# OpenTallas memory compiler (tools/mem_compiler), ASAP7 abstract view
VERSION 5.7 ;
BUSBITCHARS "[]" ;
DIVIDERCHAR "/" ;
PROPERTYDEFINITIONS
  MACRO width INTEGER ;
  MACRO depth INTEGER ;
  MACRO banks INTEGER ;
END PROPERTYDEFINITIONS
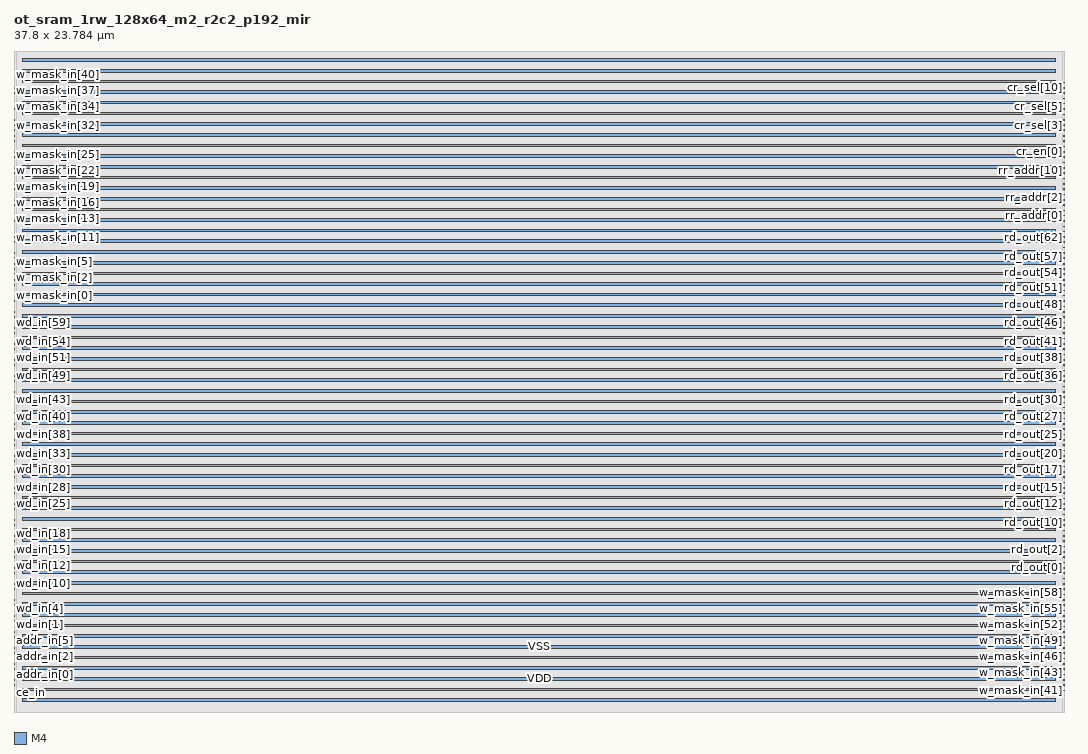
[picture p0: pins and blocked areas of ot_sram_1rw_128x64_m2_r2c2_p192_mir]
MACRO ot_sram_1rw_128x64_m2_r2c2_p192_mir
  PROPERTY width 64 ;
  PROPERTY depth 128 ;
  PROPERTY banks 1 ;
  FOREIGN ot_sram_1rw_128x64_m2_r2c2_p192_mir 0 0 ;
  SYMMETRY X Y R90 ;
  SIZE 37.800 BY 23.784 ;
  CLASS BLOCK ;
  PIN clk
    DIRECTION INPUT ;
    USE CLOCK ;
    SHAPE ABUTMENT ;
    PORT
      LAYER M4 ;
      RECT 0.000 0.768 0.024 0.792 ;
    END
  END clk
  PIN ce_in
    DIRECTION INPUT ;
    USE SIGNAL ;
    SHAPE ABUTMENT ;
    PORT
      LAYER M4 ;
      RECT 0.000 0.960 0.024 0.984 ;
    END
  END ce_in
  PIN we_in
    DIRECTION INPUT ;
    USE SIGNAL ;
    SHAPE ABUTMENT ;
    PORT
      LAYER M4 ;
      RECT 0.000 1.152 0.024 1.176 ;
    END
  END we_in
  PIN addr_in[0]
    DIRECTION INPUT ;
    USE SIGNAL ;
    SHAPE ABUTMENT ;
    PORT
      LAYER M4 ;
      RECT 0.000 1.344 0.024 1.368 ;
    END
  END addr_in[0]
  PIN addr_in[1]
    DIRECTION INPUT ;
    USE SIGNAL ;
    SHAPE ABUTMENT ;
    PORT
      LAYER M4 ;
      RECT 0.000 1.536 0.024 1.560 ;
    END
  END addr_in[1]
  PIN addr_in[2]
    DIRECTION INPUT ;
    USE SIGNAL ;
    SHAPE ABUTMENT ;
    PORT
      LAYER M4 ;
      RECT 0.000 1.728 0.024 1.752 ;
    END
  END addr_in[2]
  PIN addr_in[3]
    DIRECTION INPUT ;
    USE SIGNAL ;
    SHAPE ABUTMENT ;
    PORT
      LAYER M4 ;
      RECT 0.000 1.920 0.024 1.944 ;
    END
  END addr_in[3]
  PIN addr_in[4]
    DIRECTION INPUT ;
    USE SIGNAL ;
    SHAPE ABUTMENT ;
    PORT
      LAYER M4 ;
      RECT 0.000 2.112 0.024 2.136 ;
    END
  END addr_in[4]
  PIN addr_in[5]
    DIRECTION INPUT ;
    USE SIGNAL ;
    SHAPE ABUTMENT ;
    PORT
      LAYER M4 ;
      RECT 0.000 2.304 0.024 2.328 ;
    END
  END addr_in[5]
  PIN addr_in[6]
    DIRECTION INPUT ;
    USE SIGNAL ;
    SHAPE ABUTMENT ;
    PORT
      LAYER M4 ;
      RECT 0.000 2.496 0.024 2.520 ;
    END
  END addr_in[6]
  PIN wd_in[0]
    DIRECTION INPUT ;
    USE SIGNAL ;
    SHAPE ABUTMENT ;
    PORT
      LAYER M4 ;
      RECT 0.000 2.688 0.024 2.712 ;
    END
  END wd_in[0]
  PIN wd_in[1]
    DIRECTION INPUT ;
    USE SIGNAL ;
    SHAPE ABUTMENT ;
    PORT
      LAYER M4 ;
      RECT 0.000 2.880 0.024 2.904 ;
    END
  END wd_in[1]
  PIN wd_in[2]
    DIRECTION INPUT ;
    USE SIGNAL ;
    SHAPE ABUTMENT ;
    PORT
      LAYER M4 ;
      RECT 0.000 3.072 0.024 3.096 ;
    END
  END wd_in[2]
  PIN wd_in[3]
    DIRECTION INPUT ;
    USE SIGNAL ;
    SHAPE ABUTMENT ;
    PORT
      LAYER M4 ;
      RECT 0.000 3.264 0.024 3.288 ;
    END
  END wd_in[3]
  PIN wd_in[4]
    DIRECTION INPUT ;
    USE SIGNAL ;
    SHAPE ABUTMENT ;
    PORT
      LAYER M4 ;
      RECT 0.000 3.456 0.024 3.480 ;
    END
  END wd_in[4]
  PIN wd_in[5]
    DIRECTION INPUT ;
    USE SIGNAL ;
    SHAPE ABUTMENT ;
    PORT
      LAYER M4 ;
      RECT 0.000 3.648 0.024 3.672 ;
    END
  END wd_in[5]
  PIN wd_in[6]
    DIRECTION INPUT ;
    USE SIGNAL ;
    SHAPE ABUTMENT ;
    PORT
      LAYER M4 ;
      RECT 0.000 3.840 0.024 3.864 ;
    END
  END wd_in[6]
  PIN wd_in[7]
    DIRECTION INPUT ;
    USE SIGNAL ;
    SHAPE ABUTMENT ;
    PORT
      LAYER M4 ;
      RECT 0.000 4.032 0.024 4.056 ;
    END
  END wd_in[7]
  PIN wd_in[8]
    DIRECTION INPUT ;
    USE SIGNAL ;
    SHAPE ABUTMENT ;
    PORT
      LAYER M4 ;
      RECT 0.000 4.224 0.024 4.248 ;
    END
  END wd_in[8]
  PIN wd_in[9]
    DIRECTION INPUT ;
    USE SIGNAL ;
    SHAPE ABUTMENT ;
    PORT
      LAYER M4 ;
      RECT 0.000 4.416 0.024 4.440 ;
    END
  END wd_in[9]
  PIN wd_in[10]
    DIRECTION INPUT ;
    USE SIGNAL ;
    SHAPE ABUTMENT ;
    PORT
      LAYER M4 ;
      RECT 0.000 4.608 0.024 4.632 ;
    END
  END wd_in[10]
  PIN wd_in[11]
    DIRECTION INPUT ;
    USE SIGNAL ;
    SHAPE ABUTMENT ;
    PORT
      LAYER M4 ;
      RECT 0.000 4.800 0.024 4.824 ;
    END
  END wd_in[11]
  PIN wd_in[12]
    DIRECTION INPUT ;
    USE SIGNAL ;
    SHAPE ABUTMENT ;
    PORT
      LAYER M4 ;
      RECT 0.000 4.992 0.024 5.016 ;
    END
  END wd_in[12]
  PIN wd_in[13]
    DIRECTION INPUT ;
    USE SIGNAL ;
    SHAPE ABUTMENT ;
    PORT
      LAYER M4 ;
      RECT 0.000 5.184 0.024 5.208 ;
    END
  END wd_in[13]
  PIN wd_in[14]
    DIRECTION INPUT ;
    USE SIGNAL ;
    SHAPE ABUTMENT ;
    PORT
      LAYER M4 ;
      RECT 0.000 5.376 0.024 5.400 ;
    END
  END wd_in[14]
  PIN wd_in[15]
    DIRECTION INPUT ;
    USE SIGNAL ;
    SHAPE ABUTMENT ;
    PORT
      LAYER M4 ;
      RECT 0.000 5.568 0.024 5.592 ;
    END
  END wd_in[15]
  PIN wd_in[16]
    DIRECTION INPUT ;
    USE SIGNAL ;
    SHAPE ABUTMENT ;
    PORT
      LAYER M4 ;
      RECT 0.000 5.760 0.024 5.784 ;
    END
  END wd_in[16]
  PIN wd_in[17]
    DIRECTION INPUT ;
    USE SIGNAL ;
    SHAPE ABUTMENT ;
    PORT
      LAYER M4 ;
      RECT 0.000 5.952 0.024 5.976 ;
    END
  END wd_in[17]
  PIN wd_in[18]
    DIRECTION INPUT ;
    USE SIGNAL ;
    SHAPE ABUTMENT ;
    PORT
      LAYER M4 ;
      RECT 0.000 6.144 0.024 6.168 ;
    END
  END wd_in[18]
  PIN wd_in[19]
    DIRECTION INPUT ;
    USE SIGNAL ;
    SHAPE ABUTMENT ;
    PORT
      LAYER M4 ;
      RECT 0.000 6.336 0.024 6.360 ;
    END
  END wd_in[19]
  PIN wd_in[20]
    DIRECTION INPUT ;
    USE SIGNAL ;
    SHAPE ABUTMENT ;
    PORT
      LAYER M4 ;
      RECT 0.000 6.528 0.024 6.552 ;
    END
  END wd_in[20]
  PIN wd_in[21]
    DIRECTION INPUT ;
    USE SIGNAL ;
    SHAPE ABUTMENT ;
    PORT
      LAYER M4 ;
      RECT 0.000 6.720 0.024 6.744 ;
    END
  END wd_in[21]
  PIN wd_in[22]
    DIRECTION INPUT ;
    USE SIGNAL ;
    SHAPE ABUTMENT ;
    PORT
      LAYER M4 ;
      RECT 0.000 6.912 0.024 6.936 ;
    END
  END wd_in[22]
  PIN wd_in[23]
    DIRECTION INPUT ;
    USE SIGNAL ;
    SHAPE ABUTMENT ;
    PORT
      LAYER M4 ;
      RECT 0.000 7.104 0.024 7.128 ;
    END
  END wd_in[23]
  PIN wd_in[24]
    DIRECTION INPUT ;
    USE SIGNAL ;
    SHAPE ABUTMENT ;
    PORT
      LAYER M4 ;
      RECT 0.000 7.296 0.024 7.320 ;
    END
  END wd_in[24]
  PIN wd_in[25]
    DIRECTION INPUT ;
    USE SIGNAL ;
    SHAPE ABUTMENT ;
    PORT
      LAYER M4 ;
      RECT 0.000 7.488 0.024 7.512 ;
    END
  END wd_in[25]
  PIN wd_in[26]
    DIRECTION INPUT ;
    USE SIGNAL ;
    SHAPE ABUTMENT ;
    PORT
      LAYER M4 ;
      RECT 0.000 7.680 0.024 7.704 ;
    END
  END wd_in[26]
  PIN wd_in[27]
    DIRECTION INPUT ;
    USE SIGNAL ;
    SHAPE ABUTMENT ;
    PORT
      LAYER M4 ;
      RECT 0.000 7.872 0.024 7.896 ;
    END
  END wd_in[27]
  PIN wd_in[28]
    DIRECTION INPUT ;
    USE SIGNAL ;
    SHAPE ABUTMENT ;
    PORT
      LAYER M4 ;
      RECT 0.000 8.064 0.024 8.088 ;
    END
  END wd_in[28]
  PIN wd_in[29]
    DIRECTION INPUT ;
    USE SIGNAL ;
    SHAPE ABUTMENT ;
    PORT
      LAYER M4 ;
      RECT 0.000 8.256 0.024 8.280 ;
    END
  END wd_in[29]
  PIN wd_in[30]
    DIRECTION INPUT ;
    USE SIGNAL ;
    SHAPE ABUTMENT ;
    PORT
      LAYER M4 ;
      RECT 0.000 8.448 0.024 8.472 ;
    END
  END wd_in[30]
  PIN wd_in[31]
    DIRECTION INPUT ;
    USE SIGNAL ;
    SHAPE ABUTMENT ;
    PORT
      LAYER M4 ;
      RECT 0.000 8.640 0.024 8.664 ;
    END
  END wd_in[31]
  PIN wd_in[32]
    DIRECTION INPUT ;
    USE SIGNAL ;
    SHAPE ABUTMENT ;
    PORT
      LAYER M4 ;
      RECT 0.000 8.832 0.024 8.856 ;
    END
  END wd_in[32]
  PIN wd_in[33]
    DIRECTION INPUT ;
    USE SIGNAL ;
    SHAPE ABUTMENT ;
    PORT
      LAYER M4 ;
      RECT 0.000 9.024 0.024 9.048 ;
    END
  END wd_in[33]
  PIN wd_in[34]
    DIRECTION INPUT ;
    USE SIGNAL ;
    SHAPE ABUTMENT ;
    PORT
      LAYER M4 ;
      RECT 0.000 9.216 0.024 9.240 ;
    END
  END wd_in[34]
  PIN wd_in[35]
    DIRECTION INPUT ;
    USE SIGNAL ;
    SHAPE ABUTMENT ;
    PORT
      LAYER M4 ;
      RECT 0.000 9.408 0.024 9.432 ;
    END
  END wd_in[35]
  PIN wd_in[36]
    DIRECTION INPUT ;
    USE SIGNAL ;
    SHAPE ABUTMENT ;
    PORT
      LAYER M4 ;
      RECT 0.000 9.600 0.024 9.624 ;
    END
  END wd_in[36]
  PIN wd_in[37]
    DIRECTION INPUT ;
    USE SIGNAL ;
    SHAPE ABUTMENT ;
    PORT
      LAYER M4 ;
      RECT 0.000 9.792 0.024 9.816 ;
    END
  END wd_in[37]
  PIN wd_in[38]
    DIRECTION INPUT ;
    USE SIGNAL ;
    SHAPE ABUTMENT ;
    PORT
      LAYER M4 ;
      RECT 0.000 9.984 0.024 10.008 ;
    END
  END wd_in[38]
  PIN wd_in[39]
    DIRECTION INPUT ;
    USE SIGNAL ;
    SHAPE ABUTMENT ;
    PORT
      LAYER M4 ;
      RECT 0.000 10.176 0.024 10.200 ;
    END
  END wd_in[39]
  PIN wd_in[40]
    DIRECTION INPUT ;
    USE SIGNAL ;
    SHAPE ABUTMENT ;
    PORT
      LAYER M4 ;
      RECT 0.000 10.368 0.024 10.392 ;
    END
  END wd_in[40]
  PIN wd_in[41]
    DIRECTION INPUT ;
    USE SIGNAL ;
    SHAPE ABUTMENT ;
    PORT
      LAYER M4 ;
      RECT 0.000 10.560 0.024 10.584 ;
    END
  END wd_in[41]
  PIN wd_in[42]
    DIRECTION INPUT ;
    USE SIGNAL ;
    SHAPE ABUTMENT ;
    PORT
      LAYER M4 ;
      RECT 0.000 10.752 0.024 10.776 ;
    END
  END wd_in[42]
  PIN wd_in[43]
    DIRECTION INPUT ;
    USE SIGNAL ;
    SHAPE ABUTMENT ;
    PORT
      LAYER M4 ;
      RECT 0.000 10.944 0.024 10.968 ;
    END
  END wd_in[43]
  PIN wd_in[44]
    DIRECTION INPUT ;
    USE SIGNAL ;
    SHAPE ABUTMENT ;
    PORT
      LAYER M4 ;
      RECT 0.000 11.136 0.024 11.160 ;
    END
  END wd_in[44]
  PIN wd_in[45]
    DIRECTION INPUT ;
    USE SIGNAL ;
    SHAPE ABUTMENT ;
    PORT
      LAYER M4 ;
      RECT 0.000 11.328 0.024 11.352 ;
    END
  END wd_in[45]
  PIN wd_in[46]
    DIRECTION INPUT ;
    USE SIGNAL ;
    SHAPE ABUTMENT ;
    PORT
      LAYER M4 ;
      RECT 0.000 11.520 0.024 11.544 ;
    END
  END wd_in[46]
  PIN wd_in[47]
    DIRECTION INPUT ;
    USE SIGNAL ;
    SHAPE ABUTMENT ;
    PORT
      LAYER M4 ;
      RECT 0.000 11.712 0.024 11.736 ;
    END
  END wd_in[47]
  PIN wd_in[48]
    DIRECTION INPUT ;
    USE SIGNAL ;
    SHAPE ABUTMENT ;
    PORT
      LAYER M4 ;
      RECT 0.000 11.904 0.024 11.928 ;
    END
  END wd_in[48]
  PIN wd_in[49]
    DIRECTION INPUT ;
    USE SIGNAL ;
    SHAPE ABUTMENT ;
    PORT
      LAYER M4 ;
      RECT 0.000 12.096 0.024 12.120 ;
    END
  END wd_in[49]
  PIN wd_in[50]
    DIRECTION INPUT ;
    USE SIGNAL ;
    SHAPE ABUTMENT ;
    PORT
      LAYER M4 ;
      RECT 0.000 12.288 0.024 12.312 ;
    END
  END wd_in[50]
  PIN wd_in[51]
    DIRECTION INPUT ;
    USE SIGNAL ;
    SHAPE ABUTMENT ;
    PORT
      LAYER M4 ;
      RECT 0.000 12.480 0.024 12.504 ;
    END
  END wd_in[51]
  PIN wd_in[52]
    DIRECTION INPUT ;
    USE SIGNAL ;
    SHAPE ABUTMENT ;
    PORT
      LAYER M4 ;
      RECT 0.000 12.672 0.024 12.696 ;
    END
  END wd_in[52]
  PIN wd_in[53]
    DIRECTION INPUT ;
    USE SIGNAL ;
    SHAPE ABUTMENT ;
    PORT
      LAYER M4 ;
      RECT 0.000 12.864 0.024 12.888 ;
    END
  END wd_in[53]
  PIN wd_in[54]
    DIRECTION INPUT ;
    USE SIGNAL ;
    SHAPE ABUTMENT ;
    PORT
      LAYER M4 ;
      RECT 0.000 13.056 0.024 13.080 ;
    END
  END wd_in[54]
  PIN wd_in[55]
    DIRECTION INPUT ;
    USE SIGNAL ;
    SHAPE ABUTMENT ;
    PORT
      LAYER M4 ;
      RECT 0.000 13.248 0.024 13.272 ;
    END
  END wd_in[55]
  PIN wd_in[56]
    DIRECTION INPUT ;
    USE SIGNAL ;
    SHAPE ABUTMENT ;
    PORT
      LAYER M4 ;
      RECT 0.000 13.440 0.024 13.464 ;
    END
  END wd_in[56]
  PIN wd_in[57]
    DIRECTION INPUT ;
    USE SIGNAL ;
    SHAPE ABUTMENT ;
    PORT
      LAYER M4 ;
      RECT 0.000 13.632 0.024 13.656 ;
    END
  END wd_in[57]
  PIN wd_in[58]
    DIRECTION INPUT ;
    USE SIGNAL ;
    SHAPE ABUTMENT ;
    PORT
      LAYER M4 ;
      RECT 0.000 13.824 0.024 13.848 ;
    END
  END wd_in[58]
  PIN wd_in[59]
    DIRECTION INPUT ;
    USE SIGNAL ;
    SHAPE ABUTMENT ;
    PORT
      LAYER M4 ;
      RECT 0.000 14.016 0.024 14.040 ;
    END
  END wd_in[59]
  PIN wd_in[60]
    DIRECTION INPUT ;
    USE SIGNAL ;
    SHAPE ABUTMENT ;
    PORT
      LAYER M4 ;
      RECT 0.000 14.208 0.024 14.232 ;
    END
  END wd_in[60]
  PIN wd_in[61]
    DIRECTION INPUT ;
    USE SIGNAL ;
    SHAPE ABUTMENT ;
    PORT
      LAYER M4 ;
      RECT 0.000 14.400 0.024 14.424 ;
    END
  END wd_in[61]
  PIN wd_in[62]
    DIRECTION INPUT ;
    USE SIGNAL ;
    SHAPE ABUTMENT ;
    PORT
      LAYER M4 ;
      RECT 0.000 14.592 0.024 14.616 ;
    END
  END wd_in[62]
  PIN wd_in[63]
    DIRECTION INPUT ;
    USE SIGNAL ;
    SHAPE ABUTMENT ;
    PORT
      LAYER M4 ;
      RECT 0.000 14.784 0.024 14.808 ;
    END
  END wd_in[63]
  PIN w_mask_in[0]
    DIRECTION INPUT ;
    USE SIGNAL ;
    SHAPE ABUTMENT ;
    PORT
      LAYER M4 ;
      RECT 0.000 14.976 0.024 15.000 ;
    END
  END w_mask_in[0]
  PIN w_mask_in[1]
    DIRECTION INPUT ;
    USE SIGNAL ;
    SHAPE ABUTMENT ;
    PORT
      LAYER M4 ;
      RECT 0.000 15.168 0.024 15.192 ;
    END
  END w_mask_in[1]
  PIN w_mask_in[2]
    DIRECTION INPUT ;
    USE SIGNAL ;
    SHAPE ABUTMENT ;
    PORT
      LAYER M4 ;
      RECT 0.000 15.360 0.024 15.384 ;
    END
  END w_mask_in[2]
  PIN w_mask_in[3]
    DIRECTION INPUT ;
    USE SIGNAL ;
    SHAPE ABUTMENT ;
    PORT
      LAYER M4 ;
      RECT 0.000 15.552 0.024 15.576 ;
    END
  END w_mask_in[3]
  PIN w_mask_in[4]
    DIRECTION INPUT ;
    USE SIGNAL ;
    SHAPE ABUTMENT ;
    PORT
      LAYER M4 ;
      RECT 0.000 15.744 0.024 15.768 ;
    END
  END w_mask_in[4]
  PIN w_mask_in[5]
    DIRECTION INPUT ;
    USE SIGNAL ;
    SHAPE ABUTMENT ;
    PORT
      LAYER M4 ;
      RECT 0.000 15.936 0.024 15.960 ;
    END
  END w_mask_in[5]
  PIN w_mask_in[6]
    DIRECTION INPUT ;
    USE SIGNAL ;
    SHAPE ABUTMENT ;
    PORT
      LAYER M4 ;
      RECT 0.000 16.128 0.024 16.152 ;
    END
  END w_mask_in[6]
  PIN w_mask_in[7]
    DIRECTION INPUT ;
    USE SIGNAL ;
    SHAPE ABUTMENT ;
    PORT
      LAYER M4 ;
      RECT 0.000 16.320 0.024 16.344 ;
    END
  END w_mask_in[7]
  PIN w_mask_in[8]
    DIRECTION INPUT ;
    USE SIGNAL ;
    SHAPE ABUTMENT ;
    PORT
      LAYER M4 ;
      RECT 0.000 16.512 0.024 16.536 ;
    END
  END w_mask_in[8]
  PIN w_mask_in[9]
    DIRECTION INPUT ;
    USE SIGNAL ;
    SHAPE ABUTMENT ;
    PORT
      LAYER M4 ;
      RECT 0.000 16.704 0.024 16.728 ;
    END
  END w_mask_in[9]
  PIN w_mask_in[10]
    DIRECTION INPUT ;
    USE SIGNAL ;
    SHAPE ABUTMENT ;
    PORT
      LAYER M4 ;
      RECT 0.000 16.896 0.024 16.920 ;
    END
  END w_mask_in[10]
  PIN w_mask_in[11]
    DIRECTION INPUT ;
    USE SIGNAL ;
    SHAPE ABUTMENT ;
    PORT
      LAYER M4 ;
      RECT 0.000 17.088 0.024 17.112 ;
    END
  END w_mask_in[11]
  PIN w_mask_in[12]
    DIRECTION INPUT ;
    USE SIGNAL ;
    SHAPE ABUTMENT ;
    PORT
      LAYER M4 ;
      RECT 0.000 17.280 0.024 17.304 ;
    END
  END w_mask_in[12]
  PIN w_mask_in[13]
    DIRECTION INPUT ;
    USE SIGNAL ;
    SHAPE ABUTMENT ;
    PORT
      LAYER M4 ;
      RECT 0.000 17.472 0.024 17.496 ;
    END
  END w_mask_in[13]
  PIN w_mask_in[14]
    DIRECTION INPUT ;
    USE SIGNAL ;
    SHAPE ABUTMENT ;
    PORT
      LAYER M4 ;
      RECT 0.000 17.664 0.024 17.688 ;
    END
  END w_mask_in[14]
  PIN w_mask_in[15]
    DIRECTION INPUT ;
    USE SIGNAL ;
    SHAPE ABUTMENT ;
    PORT
      LAYER M4 ;
      RECT 0.000 17.856 0.024 17.880 ;
    END
  END w_mask_in[15]
  PIN w_mask_in[16]
    DIRECTION INPUT ;
    USE SIGNAL ;
    SHAPE ABUTMENT ;
    PORT
      LAYER M4 ;
      RECT 0.000 18.048 0.024 18.072 ;
    END
  END w_mask_in[16]
  PIN w_mask_in[17]
    DIRECTION INPUT ;
    USE SIGNAL ;
    SHAPE ABUTMENT ;
    PORT
      LAYER M4 ;
      RECT 0.000 18.240 0.024 18.264 ;
    END
  END w_mask_in[17]
  PIN w_mask_in[18]
    DIRECTION INPUT ;
    USE SIGNAL ;
    SHAPE ABUTMENT ;
    PORT
      LAYER M4 ;
      RECT 0.000 18.432 0.024 18.456 ;
    END
  END w_mask_in[18]
  PIN w_mask_in[19]
    DIRECTION INPUT ;
    USE SIGNAL ;
    SHAPE ABUTMENT ;
    PORT
      LAYER M4 ;
      RECT 0.000 18.624 0.024 18.648 ;
    END
  END w_mask_in[19]
  PIN w_mask_in[20]
    DIRECTION INPUT ;
    USE SIGNAL ;
    SHAPE ABUTMENT ;
    PORT
      LAYER M4 ;
      RECT 0.000 18.816 0.024 18.840 ;
    END
  END w_mask_in[20]
  PIN w_mask_in[21]
    DIRECTION INPUT ;
    USE SIGNAL ;
    SHAPE ABUTMENT ;
    PORT
      LAYER M4 ;
      RECT 0.000 19.008 0.024 19.032 ;
    END
  END w_mask_in[21]
  PIN w_mask_in[22]
    DIRECTION INPUT ;
    USE SIGNAL ;
    SHAPE ABUTMENT ;
    PORT
      LAYER M4 ;
      RECT 0.000 19.200 0.024 19.224 ;
    END
  END w_mask_in[22]
  PIN w_mask_in[23]
    DIRECTION INPUT ;
    USE SIGNAL ;
    SHAPE ABUTMENT ;
    PORT
      LAYER M4 ;
      RECT 0.000 19.392 0.024 19.416 ;
    END
  END w_mask_in[23]
  PIN w_mask_in[24]
    DIRECTION INPUT ;
    USE SIGNAL ;
    SHAPE ABUTMENT ;
    PORT
      LAYER M4 ;
      RECT 0.000 19.584 0.024 19.608 ;
    END
  END w_mask_in[24]
  PIN w_mask_in[25]
    DIRECTION INPUT ;
    USE SIGNAL ;
    SHAPE ABUTMENT ;
    PORT
      LAYER M4 ;
      RECT 0.000 19.776 0.024 19.800 ;
    END
  END w_mask_in[25]
  PIN w_mask_in[26]
    DIRECTION INPUT ;
    USE SIGNAL ;
    SHAPE ABUTMENT ;
    PORT
      LAYER M4 ;
      RECT 0.000 19.968 0.024 19.992 ;
    END
  END w_mask_in[26]
  PIN w_mask_in[27]
    DIRECTION INPUT ;
    USE SIGNAL ;
    SHAPE ABUTMENT ;
    PORT
      LAYER M4 ;
      RECT 0.000 20.160 0.024 20.184 ;
    END
  END w_mask_in[27]
  PIN w_mask_in[28]
    DIRECTION INPUT ;
    USE SIGNAL ;
    SHAPE ABUTMENT ;
    PORT
      LAYER M4 ;
      RECT 0.000 20.352 0.024 20.376 ;
    END
  END w_mask_in[28]
  PIN w_mask_in[29]
    DIRECTION INPUT ;
    USE SIGNAL ;
    SHAPE ABUTMENT ;
    PORT
      LAYER M4 ;
      RECT 0.000 20.544 0.024 20.568 ;
    END
  END w_mask_in[29]
  PIN w_mask_in[30]
    DIRECTION INPUT ;
    USE SIGNAL ;
    SHAPE ABUTMENT ;
    PORT
      LAYER M4 ;
      RECT 0.000 20.736 0.024 20.760 ;
    END
  END w_mask_in[30]
  PIN w_mask_in[31]
    DIRECTION INPUT ;
    USE SIGNAL ;
    SHAPE ABUTMENT ;
    PORT
      LAYER M4 ;
      RECT 0.000 20.928 0.024 20.952 ;
    END
  END w_mask_in[31]
  PIN w_mask_in[32]
    DIRECTION INPUT ;
    USE SIGNAL ;
    SHAPE ABUTMENT ;
    PORT
      LAYER M4 ;
      RECT 0.000 21.120 0.024 21.144 ;
    END
  END w_mask_in[32]
  PIN w_mask_in[33]
    DIRECTION INPUT ;
    USE SIGNAL ;
    SHAPE ABUTMENT ;
    PORT
      LAYER M4 ;
      RECT 0.000 21.312 0.024 21.336 ;
    END
  END w_mask_in[33]
  PIN w_mask_in[34]
    DIRECTION INPUT ;
    USE SIGNAL ;
    SHAPE ABUTMENT ;
    PORT
      LAYER M4 ;
      RECT 0.000 21.504 0.024 21.528 ;
    END
  END w_mask_in[34]
  PIN w_mask_in[35]
    DIRECTION INPUT ;
    USE SIGNAL ;
    SHAPE ABUTMENT ;
    PORT
      LAYER M4 ;
      RECT 0.000 21.696 0.024 21.720 ;
    END
  END w_mask_in[35]
  PIN w_mask_in[36]
    DIRECTION INPUT ;
    USE SIGNAL ;
    SHAPE ABUTMENT ;
    PORT
      LAYER M4 ;
      RECT 0.000 21.888 0.024 21.912 ;
    END
  END w_mask_in[36]
  PIN w_mask_in[37]
    DIRECTION INPUT ;
    USE SIGNAL ;
    SHAPE ABUTMENT ;
    PORT
      LAYER M4 ;
      RECT 0.000 22.080 0.024 22.104 ;
    END
  END w_mask_in[37]
  PIN w_mask_in[38]
    DIRECTION INPUT ;
    USE SIGNAL ;
    SHAPE ABUTMENT ;
    PORT
      LAYER M4 ;
      RECT 0.000 22.272 0.024 22.296 ;
    END
  END w_mask_in[38]
  PIN w_mask_in[39]
    DIRECTION INPUT ;
    USE SIGNAL ;
    SHAPE ABUTMENT ;
    PORT
      LAYER M4 ;
      RECT 0.000 22.464 0.024 22.488 ;
    END
  END w_mask_in[39]
  PIN w_mask_in[40]
    DIRECTION INPUT ;
    USE SIGNAL ;
    SHAPE ABUTMENT ;
    PORT
      LAYER M4 ;
      RECT 0.000 22.656 0.024 22.680 ;
    END
  END w_mask_in[40]
  PIN w_mask_in[41]
    DIRECTION INPUT ;
    USE SIGNAL ;
    SHAPE ABUTMENT ;
    PORT
      LAYER M4 ;
      RECT 37.776 0.768 37.800 0.792 ;
    END
  END w_mask_in[41]
  PIN w_mask_in[42]
    DIRECTION INPUT ;
    USE SIGNAL ;
    SHAPE ABUTMENT ;
    PORT
      LAYER M4 ;
      RECT 37.776 0.960 37.800 0.984 ;
    END
  END w_mask_in[42]
  PIN w_mask_in[43]
    DIRECTION INPUT ;
    USE SIGNAL ;
    SHAPE ABUTMENT ;
    PORT
      LAYER M4 ;
      RECT 37.776 1.152 37.800 1.176 ;
    END
  END w_mask_in[43]
  PIN w_mask_in[44]
    DIRECTION INPUT ;
    USE SIGNAL ;
    SHAPE ABUTMENT ;
    PORT
      LAYER M4 ;
      RECT 37.776 1.344 37.800 1.368 ;
    END
  END w_mask_in[44]
  PIN w_mask_in[45]
    DIRECTION INPUT ;
    USE SIGNAL ;
    SHAPE ABUTMENT ;
    PORT
      LAYER M4 ;
      RECT 37.776 1.536 37.800 1.560 ;
    END
  END w_mask_in[45]
  PIN w_mask_in[46]
    DIRECTION INPUT ;
    USE SIGNAL ;
    SHAPE ABUTMENT ;
    PORT
      LAYER M4 ;
      RECT 37.776 1.728 37.800 1.752 ;
    END
  END w_mask_in[46]
  PIN w_mask_in[47]
    DIRECTION INPUT ;
    USE SIGNAL ;
    SHAPE ABUTMENT ;
    PORT
      LAYER M4 ;
      RECT 37.776 1.920 37.800 1.944 ;
    END
  END w_mask_in[47]
  PIN w_mask_in[48]
    DIRECTION INPUT ;
    USE SIGNAL ;
    SHAPE ABUTMENT ;
    PORT
      LAYER M4 ;
      RECT 37.776 2.112 37.800 2.136 ;
    END
  END w_mask_in[48]
  PIN w_mask_in[49]
    DIRECTION INPUT ;
    USE SIGNAL ;
    SHAPE ABUTMENT ;
    PORT
      LAYER M4 ;
      RECT 37.776 2.304 37.800 2.328 ;
    END
  END w_mask_in[49]
  PIN w_mask_in[50]
    DIRECTION INPUT ;
    USE SIGNAL ;
    SHAPE ABUTMENT ;
    PORT
      LAYER M4 ;
      RECT 37.776 2.496 37.800 2.520 ;
    END
  END w_mask_in[50]
  PIN w_mask_in[51]
    DIRECTION INPUT ;
    USE SIGNAL ;
    SHAPE ABUTMENT ;
    PORT
      LAYER M4 ;
      RECT 37.776 2.688 37.800 2.712 ;
    END
  END w_mask_in[51]
  PIN w_mask_in[52]
    DIRECTION INPUT ;
    USE SIGNAL ;
    SHAPE ABUTMENT ;
    PORT
      LAYER M4 ;
      RECT 37.776 2.880 37.800 2.904 ;
    END
  END w_mask_in[52]
  PIN w_mask_in[53]
    DIRECTION INPUT ;
    USE SIGNAL ;
    SHAPE ABUTMENT ;
    PORT
      LAYER M4 ;
      RECT 37.776 3.072 37.800 3.096 ;
    END
  END w_mask_in[53]
  PIN w_mask_in[54]
    DIRECTION INPUT ;
    USE SIGNAL ;
    SHAPE ABUTMENT ;
    PORT
      LAYER M4 ;
      RECT 37.776 3.264 37.800 3.288 ;
    END
  END w_mask_in[54]
  PIN w_mask_in[55]
    DIRECTION INPUT ;
    USE SIGNAL ;
    SHAPE ABUTMENT ;
    PORT
      LAYER M4 ;
      RECT 37.776 3.456 37.800 3.480 ;
    END
  END w_mask_in[55]
  PIN w_mask_in[56]
    DIRECTION INPUT ;
    USE SIGNAL ;
    SHAPE ABUTMENT ;
    PORT
      LAYER M4 ;
      RECT 37.776 3.648 37.800 3.672 ;
    END
  END w_mask_in[56]
  PIN w_mask_in[57]
    DIRECTION INPUT ;
    USE SIGNAL ;
    SHAPE ABUTMENT ;
    PORT
      LAYER M4 ;
      RECT 37.776 3.840 37.800 3.864 ;
    END
  END w_mask_in[57]
  PIN w_mask_in[58]
    DIRECTION INPUT ;
    USE SIGNAL ;
    SHAPE ABUTMENT ;
    PORT
      LAYER M4 ;
      RECT 37.776 4.032 37.800 4.056 ;
    END
  END w_mask_in[58]
  PIN w_mask_in[59]
    DIRECTION INPUT ;
    USE SIGNAL ;
    SHAPE ABUTMENT ;
    PORT
      LAYER M4 ;
      RECT 37.776 4.224 37.800 4.248 ;
    END
  END w_mask_in[59]
  PIN w_mask_in[60]
    DIRECTION INPUT ;
    USE SIGNAL ;
    SHAPE ABUTMENT ;
    PORT
      LAYER M4 ;
      RECT 37.776 4.416 37.800 4.440 ;
    END
  END w_mask_in[60]
  PIN w_mask_in[61]
    DIRECTION INPUT ;
    USE SIGNAL ;
    SHAPE ABUTMENT ;
    PORT
      LAYER M4 ;
      RECT 37.776 4.608 37.800 4.632 ;
    END
  END w_mask_in[61]
  PIN w_mask_in[62]
    DIRECTION INPUT ;
    USE SIGNAL ;
    SHAPE ABUTMENT ;
    PORT
      LAYER M4 ;
      RECT 37.776 4.800 37.800 4.824 ;
    END
  END w_mask_in[62]
  PIN w_mask_in[63]
    DIRECTION INPUT ;
    USE SIGNAL ;
    SHAPE ABUTMENT ;
    PORT
      LAYER M4 ;
      RECT 37.776 4.992 37.800 5.016 ;
    END
  END w_mask_in[63]
  PIN rd_out[0]
    DIRECTION OUTPUT ;
    USE SIGNAL ;
    SHAPE ABUTMENT ;
    PORT
      LAYER M4 ;
      RECT 37.776 5.184 37.800 5.208 ;
    END
  END rd_out[0]
  PIN rd_out[1]
    DIRECTION OUTPUT ;
    USE SIGNAL ;
    SHAPE ABUTMENT ;
    PORT
      LAYER M4 ;
      RECT 37.776 5.376 37.800 5.400 ;
    END
  END rd_out[1]
  PIN rd_out[2]
    DIRECTION OUTPUT ;
    USE SIGNAL ;
    SHAPE ABUTMENT ;
    PORT
      LAYER M4 ;
      RECT 37.776 5.568 37.800 5.592 ;
    END
  END rd_out[2]
  PIN rd_out[3]
    DIRECTION OUTPUT ;
    USE SIGNAL ;
    SHAPE ABUTMENT ;
    PORT
      LAYER M4 ;
      RECT 37.776 5.760 37.800 5.784 ;
    END
  END rd_out[3]
  PIN rd_out[4]
    DIRECTION OUTPUT ;
    USE SIGNAL ;
    SHAPE ABUTMENT ;
    PORT
      LAYER M4 ;
      RECT 37.776 5.952 37.800 5.976 ;
    END
  END rd_out[4]
  PIN rd_out[5]
    DIRECTION OUTPUT ;
    USE SIGNAL ;
    SHAPE ABUTMENT ;
    PORT
      LAYER M4 ;
      RECT 37.776 6.144 37.800 6.168 ;
    END
  END rd_out[5]
  PIN rd_out[6]
    DIRECTION OUTPUT ;
    USE SIGNAL ;
    SHAPE ABUTMENT ;
    PORT
      LAYER M4 ;
      RECT 37.776 6.336 37.800 6.360 ;
    END
  END rd_out[6]
  PIN rd_out[7]
    DIRECTION OUTPUT ;
    USE SIGNAL ;
    SHAPE ABUTMENT ;
    PORT
      LAYER M4 ;
      RECT 37.776 6.528 37.800 6.552 ;
    END
  END rd_out[7]
  PIN rd_out[8]
    DIRECTION OUTPUT ;
    USE SIGNAL ;
    SHAPE ABUTMENT ;
    PORT
      LAYER M4 ;
      RECT 37.776 6.720 37.800 6.744 ;
    END
  END rd_out[8]
  PIN rd_out[9]
    DIRECTION OUTPUT ;
    USE SIGNAL ;
    SHAPE ABUTMENT ;
    PORT
      LAYER M4 ;
      RECT 37.776 6.912 37.800 6.936 ;
    END
  END rd_out[9]
  PIN rd_out[10]
    DIRECTION OUTPUT ;
    USE SIGNAL ;
    SHAPE ABUTMENT ;
    PORT
      LAYER M4 ;
      RECT 37.776 7.104 37.800 7.128 ;
    END
  END rd_out[10]
  PIN rd_out[11]
    DIRECTION OUTPUT ;
    USE SIGNAL ;
    SHAPE ABUTMENT ;
    PORT
      LAYER M4 ;
      RECT 37.776 7.296 37.800 7.320 ;
    END
  END rd_out[11]
  PIN rd_out[12]
    DIRECTION OUTPUT ;
    USE SIGNAL ;
    SHAPE ABUTMENT ;
    PORT
      LAYER M4 ;
      RECT 37.776 7.488 37.800 7.512 ;
    END
  END rd_out[12]
  PIN rd_out[13]
    DIRECTION OUTPUT ;
    USE SIGNAL ;
    SHAPE ABUTMENT ;
    PORT
      LAYER M4 ;
      RECT 37.776 7.680 37.800 7.704 ;
    END
  END rd_out[13]
  PIN rd_out[14]
    DIRECTION OUTPUT ;
    USE SIGNAL ;
    SHAPE ABUTMENT ;
    PORT
      LAYER M4 ;
      RECT 37.776 7.872 37.800 7.896 ;
    END
  END rd_out[14]
  PIN rd_out[15]
    DIRECTION OUTPUT ;
    USE SIGNAL ;
    SHAPE ABUTMENT ;
    PORT
      LAYER M4 ;
      RECT 37.776 8.064 37.800 8.088 ;
    END
  END rd_out[15]
  PIN rd_out[16]
    DIRECTION OUTPUT ;
    USE SIGNAL ;
    SHAPE ABUTMENT ;
    PORT
      LAYER M4 ;
      RECT 37.776 8.256 37.800 8.280 ;
    END
  END rd_out[16]
  PIN rd_out[17]
    DIRECTION OUTPUT ;
    USE SIGNAL ;
    SHAPE ABUTMENT ;
    PORT
      LAYER M4 ;
      RECT 37.776 8.448 37.800 8.472 ;
    END
  END rd_out[17]
  PIN rd_out[18]
    DIRECTION OUTPUT ;
    USE SIGNAL ;
    SHAPE ABUTMENT ;
    PORT
      LAYER M4 ;
      RECT 37.776 8.640 37.800 8.664 ;
    END
  END rd_out[18]
  PIN rd_out[19]
    DIRECTION OUTPUT ;
    USE SIGNAL ;
    SHAPE ABUTMENT ;
    PORT
      LAYER M4 ;
      RECT 37.776 8.832 37.800 8.856 ;
    END
  END rd_out[19]
  PIN rd_out[20]
    DIRECTION OUTPUT ;
    USE SIGNAL ;
    SHAPE ABUTMENT ;
    PORT
      LAYER M4 ;
      RECT 37.776 9.024 37.800 9.048 ;
    END
  END rd_out[20]
  PIN rd_out[21]
    DIRECTION OUTPUT ;
    USE SIGNAL ;
    SHAPE ABUTMENT ;
    PORT
      LAYER M4 ;
      RECT 37.776 9.216 37.800 9.240 ;
    END
  END rd_out[21]
  PIN rd_out[22]
    DIRECTION OUTPUT ;
    USE SIGNAL ;
    SHAPE ABUTMENT ;
    PORT
      LAYER M4 ;
      RECT 37.776 9.408 37.800 9.432 ;
    END
  END rd_out[22]
  PIN rd_out[23]
    DIRECTION OUTPUT ;
    USE SIGNAL ;
    SHAPE ABUTMENT ;
    PORT
      LAYER M4 ;
      RECT 37.776 9.600 37.800 9.624 ;
    END
  END rd_out[23]
  PIN rd_out[24]
    DIRECTION OUTPUT ;
    USE SIGNAL ;
    SHAPE ABUTMENT ;
    PORT
      LAYER M4 ;
      RECT 37.776 9.792 37.800 9.816 ;
    END
  END rd_out[24]
  PIN rd_out[25]
    DIRECTION OUTPUT ;
    USE SIGNAL ;
    SHAPE ABUTMENT ;
    PORT
      LAYER M4 ;
      RECT 37.776 9.984 37.800 10.008 ;
    END
  END rd_out[25]
  PIN rd_out[26]
    DIRECTION OUTPUT ;
    USE SIGNAL ;
    SHAPE ABUTMENT ;
    PORT
      LAYER M4 ;
      RECT 37.776 10.176 37.800 10.200 ;
    END
  END rd_out[26]
  PIN rd_out[27]
    DIRECTION OUTPUT ;
    USE SIGNAL ;
    SHAPE ABUTMENT ;
    PORT
      LAYER M4 ;
      RECT 37.776 10.368 37.800 10.392 ;
    END
  END rd_out[27]
  PIN rd_out[28]
    DIRECTION OUTPUT ;
    USE SIGNAL ;
    SHAPE ABUTMENT ;
    PORT
      LAYER M4 ;
      RECT 37.776 10.560 37.800 10.584 ;
    END
  END rd_out[28]
  PIN rd_out[29]
    DIRECTION OUTPUT ;
    USE SIGNAL ;
    SHAPE ABUTMENT ;
    PORT
      LAYER M4 ;
      RECT 37.776 10.752 37.800 10.776 ;
    END
  END rd_out[29]
  PIN rd_out[30]
    DIRECTION OUTPUT ;
    USE SIGNAL ;
    SHAPE ABUTMENT ;
    PORT
      LAYER M4 ;
      RECT 37.776 10.944 37.800 10.968 ;
    END
  END rd_out[30]
  PIN rd_out[31]
    DIRECTION OUTPUT ;
    USE SIGNAL ;
    SHAPE ABUTMENT ;
    PORT
      LAYER M4 ;
      RECT 37.776 11.136 37.800 11.160 ;
    END
  END rd_out[31]
  PIN rd_out[32]
    DIRECTION OUTPUT ;
    USE SIGNAL ;
    SHAPE ABUTMENT ;
    PORT
      LAYER M4 ;
      RECT 37.776 11.328 37.800 11.352 ;
    END
  END rd_out[32]
  PIN rd_out[33]
    DIRECTION OUTPUT ;
    USE SIGNAL ;
    SHAPE ABUTMENT ;
    PORT
      LAYER M4 ;
      RECT 37.776 11.520 37.800 11.544 ;
    END
  END rd_out[33]
  PIN rd_out[34]
    DIRECTION OUTPUT ;
    USE SIGNAL ;
    SHAPE ABUTMENT ;
    PORT
      LAYER M4 ;
      RECT 37.776 11.712 37.800 11.736 ;
    END
  END rd_out[34]
  PIN rd_out[35]
    DIRECTION OUTPUT ;
    USE SIGNAL ;
    SHAPE ABUTMENT ;
    PORT
      LAYER M4 ;
      RECT 37.776 11.904 37.800 11.928 ;
    END
  END rd_out[35]
  PIN rd_out[36]
    DIRECTION OUTPUT ;
    USE SIGNAL ;
    SHAPE ABUTMENT ;
    PORT
      LAYER M4 ;
      RECT 37.776 12.096 37.800 12.120 ;
    END
  END rd_out[36]
  PIN rd_out[37]
    DIRECTION OUTPUT ;
    USE SIGNAL ;
    SHAPE ABUTMENT ;
    PORT
      LAYER M4 ;
      RECT 37.776 12.288 37.800 12.312 ;
    END
  END rd_out[37]
  PIN rd_out[38]
    DIRECTION OUTPUT ;
    USE SIGNAL ;
    SHAPE ABUTMENT ;
    PORT
      LAYER M4 ;
      RECT 37.776 12.480 37.800 12.504 ;
    END
  END rd_out[38]
  PIN rd_out[39]
    DIRECTION OUTPUT ;
    USE SIGNAL ;
    SHAPE ABUTMENT ;
    PORT
      LAYER M4 ;
      RECT 37.776 12.672 37.800 12.696 ;
    END
  END rd_out[39]
  PIN rd_out[40]
    DIRECTION OUTPUT ;
    USE SIGNAL ;
    SHAPE ABUTMENT ;
    PORT
      LAYER M4 ;
      RECT 37.776 12.864 37.800 12.888 ;
    END
  END rd_out[40]
  PIN rd_out[41]
    DIRECTION OUTPUT ;
    USE SIGNAL ;
    SHAPE ABUTMENT ;
    PORT
      LAYER M4 ;
      RECT 37.776 13.056 37.800 13.080 ;
    END
  END rd_out[41]
  PIN rd_out[42]
    DIRECTION OUTPUT ;
    USE SIGNAL ;
    SHAPE ABUTMENT ;
    PORT
      LAYER M4 ;
      RECT 37.776 13.248 37.800 13.272 ;
    END
  END rd_out[42]
  PIN rd_out[43]
    DIRECTION OUTPUT ;
    USE SIGNAL ;
    SHAPE ABUTMENT ;
    PORT
      LAYER M4 ;
      RECT 37.776 13.440 37.800 13.464 ;
    END
  END rd_out[43]
  PIN rd_out[44]
    DIRECTION OUTPUT ;
    USE SIGNAL ;
    SHAPE ABUTMENT ;
    PORT
      LAYER M4 ;
      RECT 37.776 13.632 37.800 13.656 ;
    END
  END rd_out[44]
  PIN rd_out[45]
    DIRECTION OUTPUT ;
    USE SIGNAL ;
    SHAPE ABUTMENT ;
    PORT
      LAYER M4 ;
      RECT 37.776 13.824 37.800 13.848 ;
    END
  END rd_out[45]
  PIN rd_out[46]
    DIRECTION OUTPUT ;
    USE SIGNAL ;
    SHAPE ABUTMENT ;
    PORT
      LAYER M4 ;
      RECT 37.776 14.016 37.800 14.040 ;
    END
  END rd_out[46]
  PIN rd_out[47]
    DIRECTION OUTPUT ;
    USE SIGNAL ;
    SHAPE ABUTMENT ;
    PORT
      LAYER M4 ;
      RECT 37.776 14.208 37.800 14.232 ;
    END
  END rd_out[47]
  PIN rd_out[48]
    DIRECTION OUTPUT ;
    USE SIGNAL ;
    SHAPE ABUTMENT ;
    PORT
      LAYER M4 ;
      RECT 37.776 14.400 37.800 14.424 ;
    END
  END rd_out[48]
  PIN rd_out[49]
    DIRECTION OUTPUT ;
    USE SIGNAL ;
    SHAPE ABUTMENT ;
    PORT
      LAYER M4 ;
      RECT 37.776 14.592 37.800 14.616 ;
    END
  END rd_out[49]
  PIN rd_out[50]
    DIRECTION OUTPUT ;
    USE SIGNAL ;
    SHAPE ABUTMENT ;
    PORT
      LAYER M4 ;
      RECT 37.776 14.784 37.800 14.808 ;
    END
  END rd_out[50]
  PIN rd_out[51]
    DIRECTION OUTPUT ;
    USE SIGNAL ;
    SHAPE ABUTMENT ;
    PORT
      LAYER M4 ;
      RECT 37.776 14.976 37.800 15.000 ;
    END
  END rd_out[51]
  PIN rd_out[52]
    DIRECTION OUTPUT ;
    USE SIGNAL ;
    SHAPE ABUTMENT ;
    PORT
      LAYER M4 ;
      RECT 37.776 15.168 37.800 15.192 ;
    END
  END rd_out[52]
  PIN rd_out[53]
    DIRECTION OUTPUT ;
    USE SIGNAL ;
    SHAPE ABUTMENT ;
    PORT
      LAYER M4 ;
      RECT 37.776 15.360 37.800 15.384 ;
    END
  END rd_out[53]
  PIN rd_out[54]
    DIRECTION OUTPUT ;
    USE SIGNAL ;
    SHAPE ABUTMENT ;
    PORT
      LAYER M4 ;
      RECT 37.776 15.552 37.800 15.576 ;
    END
  END rd_out[54]
  PIN rd_out[55]
    DIRECTION OUTPUT ;
    USE SIGNAL ;
    SHAPE ABUTMENT ;
    PORT
      LAYER M4 ;
      RECT 37.776 15.744 37.800 15.768 ;
    END
  END rd_out[55]
  PIN rd_out[56]
    DIRECTION OUTPUT ;
    USE SIGNAL ;
    SHAPE ABUTMENT ;
    PORT
      LAYER M4 ;
      RECT 37.776 15.936 37.800 15.960 ;
    END
  END rd_out[56]
  PIN rd_out[57]
    DIRECTION OUTPUT ;
    USE SIGNAL ;
    SHAPE ABUTMENT ;
    PORT
      LAYER M4 ;
      RECT 37.776 16.128 37.800 16.152 ;
    END
  END rd_out[57]
  PIN rd_out[58]
    DIRECTION OUTPUT ;
    USE SIGNAL ;
    SHAPE ABUTMENT ;
    PORT
      LAYER M4 ;
      RECT 37.776 16.320 37.800 16.344 ;
    END
  END rd_out[58]
  PIN rd_out[59]
    DIRECTION OUTPUT ;
    USE SIGNAL ;
    SHAPE ABUTMENT ;
    PORT
      LAYER M4 ;
      RECT 37.776 16.512 37.800 16.536 ;
    END
  END rd_out[59]
  PIN rd_out[60]
    DIRECTION OUTPUT ;
    USE SIGNAL ;
    SHAPE ABUTMENT ;
    PORT
      LAYER M4 ;
      RECT 37.776 16.704 37.800 16.728 ;
    END
  END rd_out[60]
  PIN rd_out[61]
    DIRECTION OUTPUT ;
    USE SIGNAL ;
    SHAPE ABUTMENT ;
    PORT
      LAYER M4 ;
      RECT 37.776 16.896 37.800 16.920 ;
    END
  END rd_out[61]
  PIN rd_out[62]
    DIRECTION OUTPUT ;
    USE SIGNAL ;
    SHAPE ABUTMENT ;
    PORT
      LAYER M4 ;
      RECT 37.776 17.088 37.800 17.112 ;
    END
  END rd_out[62]
  PIN rd_out[63]
    DIRECTION OUTPUT ;
    USE SIGNAL ;
    SHAPE ABUTMENT ;
    PORT
      LAYER M4 ;
      RECT 37.776 17.280 37.800 17.304 ;
    END
  END rd_out[63]
  PIN rr_en[0]
    DIRECTION INPUT ;
    USE SIGNAL ;
    SHAPE ABUTMENT ;
    PORT
      LAYER M4 ;
      RECT 37.776 17.472 37.800 17.496 ;
    END
  END rr_en[0]
  PIN rr_en[1]
    DIRECTION INPUT ;
    USE SIGNAL ;
    SHAPE ABUTMENT ;
    PORT
      LAYER M4 ;
      RECT 37.776 17.664 37.800 17.688 ;
    END
  END rr_en[1]
  PIN rr_addr[0]
    DIRECTION INPUT ;
    USE SIGNAL ;
    SHAPE ABUTMENT ;
    PORT
      LAYER M4 ;
      RECT 37.776 17.856 37.800 17.880 ;
    END
  END rr_addr[0]
  PIN rr_addr[1]
    DIRECTION INPUT ;
    USE SIGNAL ;
    SHAPE ABUTMENT ;
    PORT
      LAYER M4 ;
      RECT 37.776 18.048 37.800 18.072 ;
    END
  END rr_addr[1]
  PIN rr_addr[2]
    DIRECTION INPUT ;
    USE SIGNAL ;
    SHAPE ABUTMENT ;
    PORT
      LAYER M4 ;
      RECT 37.776 18.240 37.800 18.264 ;
    END
  END rr_addr[2]
  PIN rr_addr[3]
    DIRECTION INPUT ;
    USE SIGNAL ;
    SHAPE ABUTMENT ;
    PORT
      LAYER M4 ;
      RECT 37.776 18.432 37.800 18.456 ;
    END
  END rr_addr[3]
  PIN rr_addr[4]
    DIRECTION INPUT ;
    USE SIGNAL ;
    SHAPE ABUTMENT ;
    PORT
      LAYER M4 ;
      RECT 37.776 18.624 37.800 18.648 ;
    END
  END rr_addr[4]
  PIN rr_addr[5]
    DIRECTION INPUT ;
    USE SIGNAL ;
    SHAPE ABUTMENT ;
    PORT
      LAYER M4 ;
      RECT 37.776 18.816 37.800 18.840 ;
    END
  END rr_addr[5]
  PIN rr_addr[6]
    DIRECTION INPUT ;
    USE SIGNAL ;
    SHAPE ABUTMENT ;
    PORT
      LAYER M4 ;
      RECT 37.776 19.008 37.800 19.032 ;
    END
  END rr_addr[6]
  PIN rr_addr[7]
    DIRECTION INPUT ;
    USE SIGNAL ;
    SHAPE ABUTMENT ;
    PORT
      LAYER M4 ;
      RECT 37.776 19.200 37.800 19.224 ;
    END
  END rr_addr[7]
  PIN rr_addr[8]
    DIRECTION INPUT ;
    USE SIGNAL ;
    SHAPE ABUTMENT ;
    PORT
      LAYER M4 ;
      RECT 37.776 19.392 37.800 19.416 ;
    END
  END rr_addr[8]
  PIN rr_addr[9]
    DIRECTION INPUT ;
    USE SIGNAL ;
    SHAPE ABUTMENT ;
    PORT
      LAYER M4 ;
      RECT 37.776 19.584 37.800 19.608 ;
    END
  END rr_addr[9]
  PIN rr_addr[10]
    DIRECTION INPUT ;
    USE SIGNAL ;
    SHAPE ABUTMENT ;
    PORT
      LAYER M4 ;
      RECT 37.776 19.776 37.800 19.800 ;
    END
  END rr_addr[10]
  PIN rr_addr[11]
    DIRECTION INPUT ;
    USE SIGNAL ;
    SHAPE ABUTMENT ;
    PORT
      LAYER M4 ;
      RECT 37.776 19.968 37.800 19.992 ;
    END
  END rr_addr[11]
  PIN cr_en[0]
    DIRECTION INPUT ;
    USE SIGNAL ;
    SHAPE ABUTMENT ;
    PORT
      LAYER M4 ;
      RECT 37.776 20.160 37.800 20.184 ;
    END
  END cr_en[0]
  PIN cr_en[1]
    DIRECTION INPUT ;
    USE SIGNAL ;
    SHAPE ABUTMENT ;
    PORT
      LAYER M4 ;
      RECT 37.776 20.352 37.800 20.376 ;
    END
  END cr_en[1]
  PIN cr_sel[0]
    DIRECTION INPUT ;
    USE SIGNAL ;
    SHAPE ABUTMENT ;
    PORT
      LAYER M4 ;
      RECT 37.776 20.544 37.800 20.568 ;
    END
  END cr_sel[0]
  PIN cr_sel[1]
    DIRECTION INPUT ;
    USE SIGNAL ;
    SHAPE ABUTMENT ;
    PORT
      LAYER M4 ;
      RECT 37.776 20.736 37.800 20.760 ;
    END
  END cr_sel[1]
  PIN cr_sel[2]
    DIRECTION INPUT ;
    USE SIGNAL ;
    SHAPE ABUTMENT ;
    PORT
      LAYER M4 ;
      RECT 37.776 20.928 37.800 20.952 ;
    END
  END cr_sel[2]
  PIN cr_sel[3]
    DIRECTION INPUT ;
    USE SIGNAL ;
    SHAPE ABUTMENT ;
    PORT
      LAYER M4 ;
      RECT 37.776 21.120 37.800 21.144 ;
    END
  END cr_sel[3]
  PIN cr_sel[4]
    DIRECTION INPUT ;
    USE SIGNAL ;
    SHAPE ABUTMENT ;
    PORT
      LAYER M4 ;
      RECT 37.776 21.312 37.800 21.336 ;
    END
  END cr_sel[4]
  PIN cr_sel[5]
    DIRECTION INPUT ;
    USE SIGNAL ;
    SHAPE ABUTMENT ;
    PORT
      LAYER M4 ;
      RECT 37.776 21.504 37.800 21.528 ;
    END
  END cr_sel[5]
  PIN cr_sel[6]
    DIRECTION INPUT ;
    USE SIGNAL ;
    SHAPE ABUTMENT ;
    PORT
      LAYER M4 ;
      RECT 37.776 21.696 37.800 21.720 ;
    END
  END cr_sel[6]
  PIN cr_sel[7]
    DIRECTION INPUT ;
    USE SIGNAL ;
    SHAPE ABUTMENT ;
    PORT
      LAYER M4 ;
      RECT 37.776 21.888 37.800 21.912 ;
    END
  END cr_sel[7]
  PIN cr_sel[8]
    DIRECTION INPUT ;
    USE SIGNAL ;
    SHAPE ABUTMENT ;
    PORT
      LAYER M4 ;
      RECT 37.776 22.080 37.800 22.104 ;
    END
  END cr_sel[8]
  PIN cr_sel[9]
    DIRECTION INPUT ;
    USE SIGNAL ;
    SHAPE ABUTMENT ;
    PORT
      LAYER M4 ;
      RECT 37.776 22.272 37.800 22.296 ;
    END
  END cr_sel[9]
  PIN cr_sel[10]
    DIRECTION INPUT ;
    USE SIGNAL ;
    SHAPE ABUTMENT ;
    PORT
      LAYER M4 ;
      RECT 37.776 22.464 37.800 22.488 ;
    END
  END cr_sel[10]
  PIN cr_sel[11]
    DIRECTION INPUT ;
    USE SIGNAL ;
    SHAPE ABUTMENT ;
    PORT
      LAYER M4 ;
      RECT 37.776 22.656 37.800 22.680 ;
    END
  END cr_sel[11]
  PIN VDD
    DIRECTION INOUT ;
    USE POWER ;
    PORT
      LAYER M4 ;
      RECT 0.300 0.384 37.500 0.480 ;
      RECT 0.300 1.152 37.500 1.248 ;
      RECT 0.300 1.920 37.500 2.016 ;
      RECT 0.300 2.688 37.500 2.784 ;
      RECT 0.300 3.456 37.500 3.552 ;
      RECT 0.300 4.224 37.500 4.320 ;
      RECT 0.300 4.992 37.500 5.088 ;
      RECT 0.300 5.760 37.500 5.856 ;
      RECT 0.300 6.528 37.500 6.624 ;
      RECT 0.300 7.296 37.500 7.392 ;
      RECT 0.300 8.064 37.500 8.160 ;
      RECT 0.300 8.832 37.500 8.928 ;
      RECT 0.300 9.600 37.500 9.696 ;
      RECT 0.300 10.368 37.500 10.464 ;
      RECT 0.300 11.136 37.500 11.232 ;
      RECT 0.300 11.904 37.500 12.000 ;
      RECT 0.300 12.672 37.500 12.768 ;
      RECT 0.300 13.440 37.500 13.536 ;
      RECT 0.300 14.208 37.500 14.304 ;
      RECT 0.300 14.976 37.500 15.072 ;
      RECT 0.300 15.744 37.500 15.840 ;
      RECT 0.300 16.512 37.500 16.608 ;
      RECT 0.300 17.280 37.500 17.376 ;
      RECT 0.300 18.048 37.500 18.144 ;
      RECT 0.300 18.816 37.500 18.912 ;
      RECT 0.300 19.584 37.500 19.680 ;
      RECT 0.300 20.352 37.500 20.448 ;
      RECT 0.300 21.120 37.500 21.216 ;
      RECT 0.300 21.888 37.500 21.984 ;
      RECT 0.300 22.656 37.500 22.752 ;
      RECT 0.300 23.424 37.500 23.520 ;
    END
  END VDD
  PIN VSS
    DIRECTION INOUT ;
    USE GROUND ;
    PORT
      LAYER M4 ;
      RECT 0.300 0.768 37.500 0.864 ;
      RECT 0.300 1.536 37.500 1.632 ;
      RECT 0.300 2.304 37.500 2.400 ;
      RECT 0.300 3.072 37.500 3.168 ;
      RECT 0.300 3.840 37.500 3.936 ;
      RECT 0.300 4.608 37.500 4.704 ;
      RECT 0.300 5.376 37.500 5.472 ;
      RECT 0.300 6.144 37.500 6.240 ;
      RECT 0.300 6.912 37.500 7.008 ;
      RECT 0.300 7.680 37.500 7.776 ;
      RECT 0.300 8.448 37.500 8.544 ;
      RECT 0.300 9.216 37.500 9.312 ;
      RECT 0.300 9.984 37.500 10.080 ;
      RECT 0.300 10.752 37.500 10.848 ;
      RECT 0.300 11.520 37.500 11.616 ;
      RECT 0.300 12.288 37.500 12.384 ;
      RECT 0.300 13.056 37.500 13.152 ;
      RECT 0.300 13.824 37.500 13.920 ;
      RECT 0.300 14.592 37.500 14.688 ;
      RECT 0.300 15.360 37.500 15.456 ;
      RECT 0.300 16.128 37.500 16.224 ;
      RECT 0.300 16.896 37.500 16.992 ;
      RECT 0.300 17.664 37.500 17.760 ;
      RECT 0.300 18.432 37.500 18.528 ;
      RECT 0.300 19.200 37.500 19.296 ;
      RECT 0.300 19.968 37.500 20.064 ;
      RECT 0.300 20.736 37.500 20.832 ;
      RECT 0.300 21.504 37.500 21.600 ;
      RECT 0.300 22.272 37.500 22.368 ;
      RECT 0.300 23.040 37.500 23.136 ;
    END
  END VSS
  OBS
    LAYER M1 ;
    RECT 0 0 37.800 23.784 ;
    LAYER M2 ;
    RECT 0 0 37.800 23.784 ;
    LAYER M3 ;
    RECT 0 0 37.800 23.784 ;
    LAYER M4 ;
    RECT 0.072 0 37.728 23.784 ;
  END
END ot_sram_1rw_128x64_m2_r2c2_p192_mir

END LIBRARY
